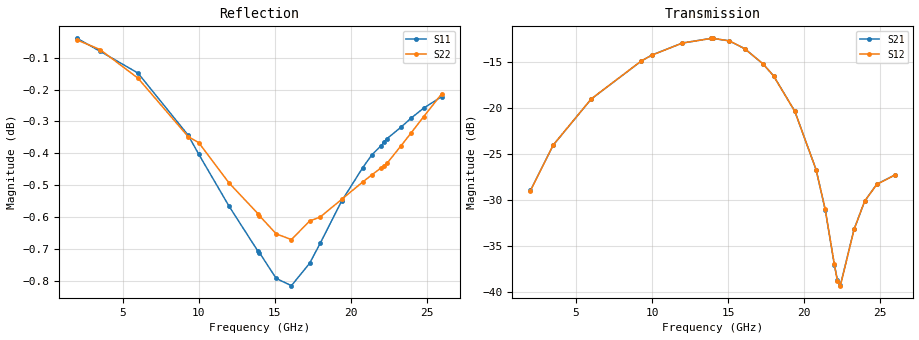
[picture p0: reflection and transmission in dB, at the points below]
! CHUO DENSHI KOGYO Co.,Ltd.
! 26. October 2020
! CKRF7613MM34_RT5880
! N-channel HJ-FET
! Vds = 0 V, Vgs = -2.5 V
# Hz S  MA  R 50
!	f	S11	S21	S12	S22
!	Hz	MAG	ANG	MAG	ANG	MAG	ANG	MAG	ANG
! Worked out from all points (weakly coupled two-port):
!   241 points, 2 GHz to 26 GHz, reference 50 ohm
!   highest |S21| = -12.39 dB at 14 GHz (marker M1); lowest = -39.3 dB at 22.4 GHz (marker M2)
!   lowest |S11| = -0.8 dB at 16.1 GHz (marker M3), VSWR 21.33, Z = 2.35 - j2.7 ohm
!   |S11| at or under -10 dB: nowhere
!   |S22| runs from -0.7 to 0.0 dB; largest |S21 - S12| = 0.00068
!   S11 on the Smith chart (normalised r, x): 2 GHz: 0.16, -8.37; 9.3 GHz: 0.06, -1.36; 13.9 GHz: 0.05, -0.42; 17.3 GHz: 0.04, +0.15; 20.8 GHz: 0.04, +0.82; 26 GHz: 0.10, +2.58
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2e9  0.9955 -13.6  0.03561 75.6  0.03549 75.5  0.9949 -14.1
3.5e9  0.9909 -24.1  0.06293 64.9  0.063 64.9  0.9915 -24.9
6e9  0.9831 -42.8  0.1122 45.5  0.1123 45.4  0.9813 -44.9
9.3e9  0.9613 -72.7  0.1808 13.6  0.181 13.6  0.9608 -76.7
1e10  0.9547 -80.3  0.1949 5.9  0.1947 5.9  0.9587 -84.3
1.2e10  0.9369 -105.0  0.2265 -18.7  0.2266 -18.8  0.9448 -108.4
1.39e10  0.9218 -134.0  0.2402 -45.9  0.24 -46.0  0.9344 -133.8
1.4e10  0.9213 -135.7  0.2402 -47.5  0.2402 -47.6  0.9337 -135.2
1.51e10  0.9128 -155.2  0.2326 -66.1  0.2327 -66.2  0.9276 -150.9
1.61e10  0.9104 -173.8  0.2109 -83.9  0.211 -83.9  0.9257 -165.6
1.73e10  0.9178 163.2  0.1746 -104.8  0.1746 -104.8  0.9319 175.7
1.8e10  0.9245 149.7  0.1501 -117.7  0.15 -117.8  0.9333 164.4
1.94e10  0.9386 124.2  0.09606 -143.8  0.09607 -143.8  0.9392 141.5
2.08e10  0.9501 101.4  0.04615 -174.0  0.04615 -174.0  0.9452 118.3
2.14e10  0.9545 92.6  0.02797 167.5  0.02805 167.5  0.9476 108.5
2.2e10  0.9576 84.4  0.01403 130.0  0.0141 130.2  0.95 98.9
2.22e10  0.9588 81.9  0.01155 107.1  0.01146 107.0  0.9508 95.8
2.24e10  0.9601 79.3  0.01084 79.5  0.01076 80.1  0.9516 92.6
2.33e10  0.964 68.5  0.02184 11.1  0.02181 10.9  0.9575 79.1
2.4e10  0.9673 61.0  0.03111 -7.6  0.03119 -7.8  0.9622 69.1
2.48e10  0.9707 53.0  0.03855 -21.7  0.03839 -21.9  0.9677 58.3
2.6e10  0.9748 42.3  0.04324 -37.4  0.04326 -37.6  0.9758 43.7
